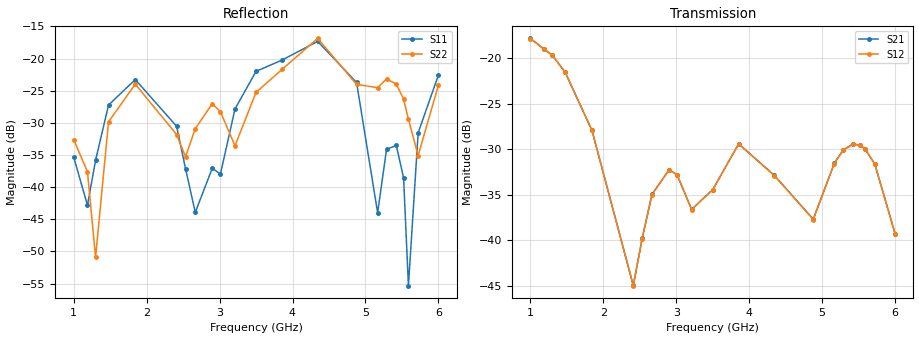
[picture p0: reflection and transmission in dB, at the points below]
!Agilent Technologies,E8364B,MY43040528,A.07.50.67
!Agilent E8364B: A.07.50.67
!Date: Sunday, March 01, 2026 23:20:21
!Correction: S11(Full 2 Port(1,2))
!S21(Full 2 Port(1,2))
!S12(Full 2 Port(1,2))
!S22(Full 2 Port(1,2))
!S2P File: Measurements: S11, S21, S12, S22:
# Hz S  dB  R 50
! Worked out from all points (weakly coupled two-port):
!   451 points, 1 GHz to 6 GHz, reference 50 ohm
!   highest |S21| = -17.80 dB at 1 GHz (marker M1); lowest = -45.0 dB at 2.411 GHz (marker M2)
!   lowest |S11| = -55.3 dB at 5.589 GHz (marker M3), VSWR 1.00, Z = 50 - j0.169 ohm
!   |S11| at or under -10 dB: start of sweep to end of sweep
!   |S22| runs from -50.9 to -16.8 dB; largest |S21 - S12| = 0.0005
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1e9  -35.32 -0.1  -17.80 29.4  -17.83 29.5  -32.59 -14.3
1.188889e9  -42.82 -61.4  -18.99 -27.1  -19.02 -27.1  -37.59 -28.4
1.3e9  -35.82 -131.9  -19.63 -63.3  -19.67 -63.2  -50.91 -135.7
1.477778e9  -27.22 169.1  -21.53 -123.1  -21.55 -123.1  -29.83 88.0
1.844444e9  -23.26 84.0  -27.91 120.9  -27.94 121.0  -23.98 -8.8
2.411111e9  -30.53 -22.1  -44.98 -124.3  -45.02 -124.3  -31.81 -99.7
2.533333e9  -37.13 -60.2  -39.79 132.5  -39.84 132.6  -35.27 -81.2
2.666667e9  -43.92 161.9  -34.98 67.0  -35.02 67.1  -30.90 -65.3
2.9e9  -37.05 90.9  -32.27 -27.9  -32.30 -27.9  -27.02 -110.0
3.011111e9  -37.98 110.6  -32.79 -69.3  -32.82 -69.3  -28.25 -134.0
3.211111e9  -27.84 118.4  -36.62 -127.5  -36.65 -127.4  -33.56 -127.8
3.5e9  -21.98 68.2  -34.44 -155.6  -34.47 -155.6  -25.25 -130.6
3.855556e9  -20.23 27.7  -29.40 82.5  -29.44 82.5  -21.69 -165.9
4.344444e9  -17.32 -47.9  -32.88 -94.5  -32.91 -94.5  -16.85 111.5
4.877778e9  -23.70 -151.7  -37.70 -2.2  -37.74 -2.2  -24.01 22.9
5.166667e9  -43.99 -110.0  -31.54 -153.5  -31.58 -153.5  -24.52 34.2
5.288889e9  -34.10 -93.0  -30.08 152.1  -30.13 152.0  -23.16 14.2
5.422222e9  -33.51 -120.1  -29.42 94.6  -29.46 94.5  -23.97 -13.7
5.522222e9  -38.54 -136.0  -29.56 52.4  -29.59 52.3  -26.29 -33.7
5.588889e9  -55.33 -99.0  -29.97 24.7  -30.00 24.6  -29.45 -41.4
5.722222e9  -31.54 -20.0  -31.63 -29.1  -31.67 -29.1  -35.08 3.7
6e9  -22.56 -75.4  -39.28 -117.4  -39.32 -117.4  -24.12 -3.7
